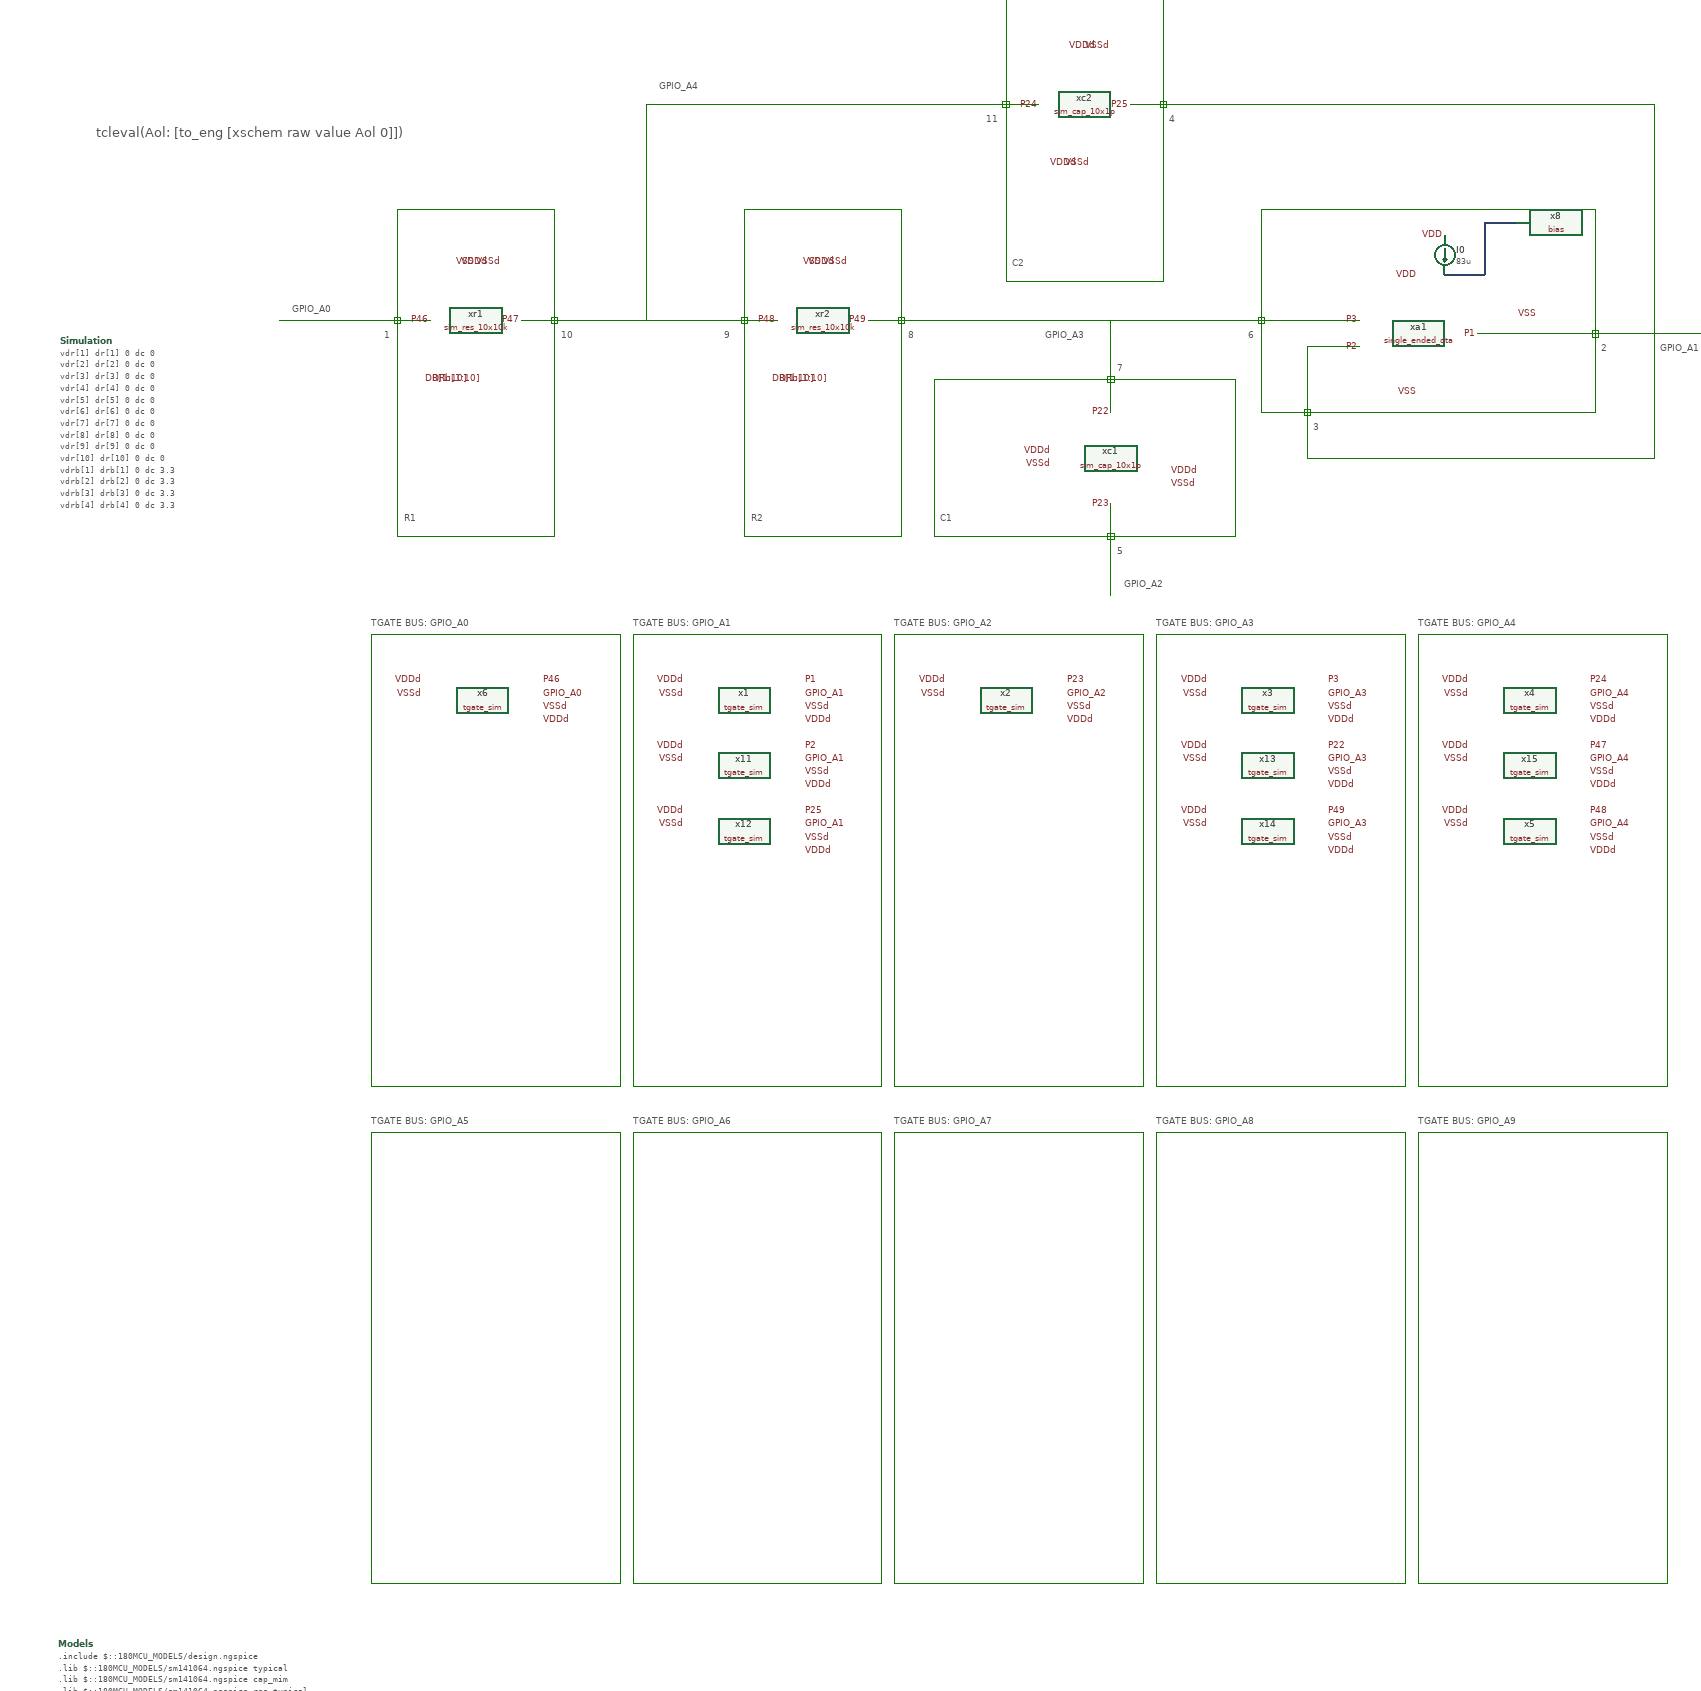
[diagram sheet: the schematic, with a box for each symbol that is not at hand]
v {xschem version=3.4.7 file_version=1.2}
G {}
K {}
V {}
S {}
E {}
L 4 1930 -1930 1930 -1830 {dash=10}
L 4 2190 -1950 2370 -1950 {dash=10}
L 4 1930 -1930 2010 -1930 {dash=10}
L 4 1860 -1970 2010 -1970 {dash=10}
L 4 730 -1970 780 -1970 {dash=10}
L 4 540 -1970 590 -1970 {dash=10}
L 4 2370 -1950 2550 -1950 {dash=10}
L 4 2460 -1950 2460 -1760 {dash=10}
L 4 1930 -1830 1930 -1760 {dash=10}
L 4 1930 -1760 2460 -1760 {dash=10}
L 4 1310 -1970 1860 -1970 {dash=10
}
L 4 780 -1970 1070 -1970 {dash=10
}
L 4 1630 -1880 1630 -1830 {dash=10}
L 4 1630 -1690 1630 -1640 {dash=10}
L 4 1630 -1970 1630 -1880 {dash=10}
L 4 1630 -1640 1630 -1550 {dash=10}
L 4 1470 -2300 1520 -2300 {dash=10}
L 4 1660 -2300 1710 -2300 {dash=10}
L 4 920 -2300 1470 -2300 {dash=10}
L 4 1710 -2300 2460 -2300 {dash=10}
L 4 920 -2300 920 -1970 {dash=10}
L 4 2460 -2300 2460 -1950 {dash=10}
L 4 360 -1970 540 -1970 {dash=10}
L 4 1260 -1970 1310 -1970 {dash=10}
L 4 1070 -1970 1120 -1970 {dash=10}
B 2 2650 -580 3450 -180 {flags=graph
y1=-2.8493778
y2=0.7426882
ypos1=0
ypos2=2
divy=5
subdivy=1
unity=1
x2=15.040264
divx=5
subdivx=8
xlabmag=1.0
ylabmag=1.0
node="\\"R=10k; gpio_a1 db20()\\"%0
\\"R=20k; gpio_a1 db20()\\"%1
\\"R=30k; gpio_a1 db20()\\"%2
\\"R=40k; gpio_a1 db20()\\"%3
\\"R=50k; gpio_a1 db20()\\"%4
\\"R=60k; gpio_a1 db20()\\"%5
\\"R=70k; gpio_a1 db20()\\"%6
\\"R=80k; gpio_a1 db20()\\"%7
\\"R=90k; gpio_a1 db20()\\"%8
\\"R=100k; gpio_a1 db20()\\"%9"
color="4 5 6 7 8 9 10 11 12 13"
dataset=-1
unitx=1
logx=1
logy=0
x1=-4.9302539
hcursor1_y=-3
}
B 4 1925 -1835 1935 -1825 {}
B 4 2365 -1955 2375 -1945 {}
B 4 1855 -1975 1865 -1965 {}
B 4 1305 -1975 1315 -1965 {}
B 4 1065 -1975 1075 -1965 {}
B 4 775 -1975 785 -1965 {}
B 4 1625 -1885 1635 -1875 {}
B 4 1625 -1645 1635 -1635 {}
B 4 1465 -2305 1475 -2295 {}
B 4 1705 -2305 1715 -2295 {}
B 4 535 -1975 545 -1965 {}
P 4 5 1860 -2140 1860 -1830 2370 -1830 2370 -2140 1860 -2140 {}
P 4 5 1070 -2140 1070 -1640 1310 -1640 1310 -2140 1070 -2140 {}
P 4 5 540 -2140 540 -1640 780 -1640 780 -2140 540 -2140 {}
P 4 5 1360 -1880 1360 -1640 1820 -1640 1820 -1880 1360 -1880 {}
P 4 5 1470 -2030 1710 -2030 1710 -2490 1470 -2490 1470 -2030 {}
P 4 5 500 -1490 500 -800 880 -800 880 -1490 500 -1490 {}
P 4 5 900 -1490 900 -800 1280 -800 1280 -1490 900 -1490 {}
P 4 5 1300 -1490 1300 -800 1680 -800 1680 -1490 1300 -1490 {}
P 4 5 1700 -1490 1700 -800 2080 -800 2080 -1490 1700 -1490 {}
P 4 5 2100 -1490 2100 -800 2480 -800 2480 -1490 2100 -1490 {}
P 4 5 500 -730 500 -40 880 -40 880 -730 500 -730 {}
P 4 5 900 -730 900 -40 1280 -40 1280 -730 900 -730 {}
P 4 5 1300 -730 1300 -40 1680 -40 1680 -730 1300 -730 {}
P 4 5 1700 -730 1700 -40 2080 -40 2080 -730 1700 -730 {}
P 4 5 2100 -730 2100 -40 2480 -40 2480 -730 2100 -730 {}
T {GPIO_A1} 2470 -1940 0 0 0.4 0.4 {}
T {GPIO_A3} 1530 -1960 0 0 0.4 0.4 {}
T {GPIO_A4} 940 -2340 0 0 0.4 0.4 {}
T {1} 520 -1960 0 0 0.3 0.3 {layer=4}
T {GPIO_A2} 1650 -1580 0 0 0.4 0.4 {}
T {GPIO_A0} 380 -2000 0 0 0.4 0.4 {}
T {2} 2380 -1940 0 0 0.3 0.3 {layer=4}
T {3} 1940 -1820 0 0 0.3 0.3 {layer=4}
T {4} 1720 -2290 0 0 0.3 0.3 {layer=4}
T {5} 1640 -1630 0 0 0.3 0.3 {layer=4}
T {6} 1840 -1960 0 0 0.3 0.3 {layer=4}
T {7} 1640 -1910 0 0 0.3 0.3 {layer=4}
T {8} 1320 -1960 0 0 0.3 0.3 {layer=4}
T {9} 1040 -1960 0 0 0.3 0.3 {layer=4}
T {10} 790 -1960 0 0 0.3 0.3 {layer=4}
T {11} 1440 -2290 0 0 0.3 0.3 {layer=4}
T {R1} 550 -1680 0 0 0.4 0.4 {}
T {C1} 1370 -1680 0 0 0.4 0.4 {}
T {C2} 1480 -2070 0 0 0.4 0.4 {}
T {TGATE BUS: GPIO_A0} 500 -1520 0 0 0.4 0.4 {}
T {TGATE BUS: GPIO_A1} 900 -1520 0 0 0.4 0.4 {}
T {TGATE BUS: GPIO_A2} 1300 -1520 0 0 0.4 0.4 {}
T {TGATE BUS: GPIO_A3} 1700 -1520 0 0 0.4 0.4 {}
T {TGATE BUS: GPIO_A4} 2100 -1520 0 0 0.4 0.4 {}
T {TGATE BUS: GPIO_A5} 500 -760 0 0 0.4 0.4 {}
T {TGATE BUS: GPIO_A6} 900 -760 0 0 0.4 0.4 {}
T {TGATE BUS: GPIO_A7} 1300 -760 0 0 0.4 0.4 {}
T {TGATE BUS: GPIO_A8} 1700 -760 0 0 0.4 0.4 {}
T {TGATE BUS: GPIO_A9} 2100 -760 0 0 0.4 0.4 {}
T {R2} 1080 -1680 0 0 0.4 0.4 {}
T {tcleval(Aol: [to_eng [xschem raw value Aol 0]])} 80 -2270 0 0 0.6 0.6 {floater=1}
N 2140 -2040 2200 -2040 {lab=#net1}
N 2200 -2120 2200 -2040 {lab=#net1}
N 2200 -2120 2250 -2120 {lab=#net1}
C {libs/core_analog/single_ended_ota/single_ended_ota.sym} 2100 -1950 0 0 {name=xa1}
C {libs/core_switch_matrix/tgate_sim/tgate_sim.sym} 670 -1390 0 0 {name=x6}
C {lab_pin.sym} 2190 -1950 3 1 {name=p1 sig_type=std_logic lab=P1}
C {lab_pin.sym} 2010 -1930 3 0 {name=p2 sig_type=std_logic lab=P2}
C {lab_pin.sym} 2100 -1860 0 0 {name=p23 sig_type=std_logic lab=VSS}
C {lab_pin.sym} 2100 -2040 0 0 {name=p24 sig_type=std_logic lab=VDD}
C {libs/core_passive_array/sim_cap_10x1p/sim_cap_10x1p.sym} 1630 -1760 0 0 {name=xc1}
C {lab_pin.sym} 1630 -1830 0 0 {name=p52 sig_type=std_logic lab=P22}
C {lab_pin.sym} 1630 -1690 0 0 {name=p53 sig_type=std_logic lab=P23}
C {lab_pin.sym} 1720 -1740 0 1 {name=p54 sig_type=std_logic lab=VDDd}
C {lab_pin.sym} 1720 -1720 0 1 {name=p55 sig_type=std_logic lab=VSSd}
C {lab_pin.sym} 580 -1420 0 0 {name=p68 sig_type=std_logic lab=VDDd}
C {lab_pin.sym} 580 -1400 0 0 {name=p69 sig_type=std_logic lab=VSSd}
C {lab_pin.sym} 760 -1420 0 1 {name=p70 sig_type=std_logic lab=P46}
C {lab_pin.sym} 760 -1400 0 1 {name=p71 sig_type=std_logic lab=GPIO_A0}
C {lab_pin.sym} 760 -1360 0 1 {name=p72 sig_type=std_logic lab=VDDd}
C {lab_pin.sym} 760 -1380 0 1 {name=p73 sig_type=std_logic lab=VSSd}
C {isource.sym} 2140 -2070 0 0 {name=I0 value=83u}
C {lab_pin.sym} 2140 -2100 0 0 {name=p191 sig_type=std_logic lab=VDD}
C {devices/code_shown.sym} 25 -1938.75 0 0 {name=Simulation only_toplevel=false value="
vdr[1] dr[1] 0 dc 0
vdr[2] dr[2] 0 dc 0
vdr[3] dr[3] 0 dc 0
vdr[4] dr[4] 0 dc 0
vdr[5] dr[5] 0 dc 0

vdr[6] dr[6] 0 dc 0
vdr[7] dr[7] 0 dc 0
vdr[8] dr[8] 0 dc 0
vdr[9] dr[9] 0 dc 0
vdr[10] dr[10] 0 dc 0

vdrb[1] drb[1] 0 dc 3.3
vdrb[2] drb[2] 0 dc 3.3
vdrb[3] drb[3] 0 dc 3.3
vdrb[4] drb[4] 0 dc 3.3
vdrb[5] drb[5] 0 dc 3.3

vdrb[6] drb[6] 0 dc 3.3
vdrb[7] drb[7] 0 dc 3.3
vdrb[8] drb[8] 0 dc 3.3
vdrb[9] drb[9] 0 dc 3.3
vdrb[10] drb[10] 0 dc 3.3


vvdd VDD 0 dc 3.3
vvss VSS 0 dc 0

vvddd VDDd 0 dc 3.3
vvssd VSSd 0 dc 0

vgpio_a2 GPIO_A2 0 dc 0
vgpio_a0 GPIO_A0 0 dc 1.65 ac 1

.nodeset all=3.3
.control
alter vdr[1] = 3.3
alter vdrb[1] = 0
save GPIO_A1
ac dec 1000 1 100e6
write sim_lk_lpf_2ord_4psv.raw
set appendwrite

reset
alter vdr[2] = 3.3
alter vdrb[2] = 0
save GPIO_A1
ac dec 1000 1 100e6
write sim_lk_lpf_2ord_4psv.raw

reset
alter vdr[3] = 3.3
alter vdrb[3] = 0
save GPIO_A1
ac dec 1000 1 100e6
write sim_lk_lpf_2ord_4psv.raw

reset
alter vdr[4] = 3.3
alter vdrb[4] = 0
save GPIO_A1
ac dec 1000 1 100e6
write sim_lk_lpf_2ord_4psv.raw

reset
alter vdr[5] = 3.3
alter vdrb[5] = 0
save GPIO_A1
ac dec 1000 1 100e6
write sim_lk_lpf_2ord_4psv.raw

reset
alter vdr[6] = 3.3
alter vdrb[6] = 0
save GPIO_A1
ac dec 1000 1 100e6
write sim_lk_lpf_2ord_4psv.raw

reset
alter vdr[7] = 3.3
alter vdrb[7] = 0
save GPIO_A1
ac dec 1000 1 100e6
write sim_lk_lpf_2ord_4psv.raw

reset
alter vdr[8] = 3.3
alter vdrb[8] = 0
save GPIO_A1
ac dec 1000 1 100e6
write sim_lk_lpf_2ord_4psv.raw

reset
alter vdr[9] = 3.3
alter vdrb[9] = 0
save GPIO_A1
ac dec 1000 1 100e6
write sim_lk_lpf_2ord_4psv.raw

reset
alter vdr[10] = 3.3
alter vdrb[10] = 0
save GPIO_A1
ac dec 1000 1 100e6
write sim_lk_lpf_2ord_4psv.raw
.endc
"}
C {devices/code_shown.sym} 22.5 52.5 0 0 {name=Models only_toplevel=false
format="tcleval( @value )"
value="
.include $::180MCU_MODELS/design.ngspice
.lib $::180MCU_MODELS/sm141064.ngspice typical
.lib $::180MCU_MODELS/sm141064.ngspice cap_mim
.lib $::180MCU_MODELS/sm141064.ngspice res_typical
.lib $::180MCU_MODELS/sm141064.ngspice moscap_typical
.lib $::180MCU_MODELS/sm141064.ngspice mimcap_typical
.include /foss/pdks/gf180mcuD/libs.ref/gf180mcu_fd_sc_mcu9t5v0/spice/gf180mcu_fd_sc_mcu9t5v0.spice
"}
C {launcher.sym} 2710 -150 0 0 {name=h5
descr="load waves" 
tclcommand="xschem raw_read $netlist_dir/sim_filter_block_tgate.raw ac"
}
C {lab_pin.sym} 2010 -1970 1 0 {name=p6 sig_type=std_logic lab=P3}
C {libs/core_passive_array/sim_res_10x10k/sim_res_10x10k.sym} 660 -1970 3 0 {name=xr1}
C {lab_pin.sym} 590 -1970 3 0 {name=p204 sig_type=std_logic lab=P46}
C {lab_pin.sym} 730 -1970 3 0 {name=p205 sig_type=std_logic lab=P47}
C {lab_pin.sym} 660 -2060 3 1 {name=p211 sig_type=std_logic lab=VSS}
C {lab_pin.sym} 680 -2060 3 1 {name=p212 sig_type=std_logic lab=VDDd}
C {lab_pin.sym} 700 -2060 3 1 {name=p213 sig_type=std_logic lab=VSSd}
C {lab_pin.sym} 650 -1880 3 0 {name=p214 sig_type=std_logic lab="DR[1:10]"}
C {lab_pin.sym} 670 -1880 3 0 {name=p215 sig_type=std_logic lab="DRb[1:10]"}
C {libs/core_passive_array/sim_cap_10x1p/sim_cap_10x1p.sym} 1590 -2300 3 0 {name=xc2}
C {lab_pin.sym} 1520 -2300 3 0 {name=p218 sig_type=std_logic lab=P24}
C {lab_pin.sym} 1660 -2300 3 0 {name=p219 sig_type=std_logic lab=P25}
C {lab_pin.sym} 1610 -2390 3 1 {name=p220 sig_type=std_logic lab=VDDd}
C {lab_pin.sym} 1630 -2390 3 1 {name=p221 sig_type=std_logic lab=VSSd}
C {libs/core_switch_matrix/tgate_sim/tgate_sim.sym} 1070 -1390 0 0 {name=x1}
C {lab_pin.sym} 980 -1420 0 0 {name=p3 sig_type=std_logic lab=VDDd}
C {lab_pin.sym} 980 -1400 0 0 {name=p4 sig_type=std_logic lab=VSSd}
C {lab_pin.sym} 1160 -1420 0 1 {name=p5 sig_type=std_logic lab=P1}
C {lab_pin.sym} 1160 -1400 0 1 {name=p7 sig_type=std_logic lab=GPIO_A1}
C {lab_pin.sym} 1160 -1360 0 1 {name=p8 sig_type=std_logic lab=VDDd}
C {lab_pin.sym} 1160 -1380 0 1 {name=p9 sig_type=std_logic lab=VSSd}
C {libs/core_switch_matrix/tgate_sim/tgate_sim.sym} 1470 -1390 0 0 {name=x2}
C {lab_pin.sym} 1380 -1420 0 0 {name=p10 sig_type=std_logic lab=VDDd}
C {lab_pin.sym} 1380 -1400 0 0 {name=p11 sig_type=std_logic lab=VSSd}
C {lab_pin.sym} 1560 -1420 0 1 {name=p16 sig_type=std_logic lab=P23}
C {lab_pin.sym} 1560 -1400 0 1 {name=p17 sig_type=std_logic lab=GPIO_A2}
C {lab_pin.sym} 1560 -1360 0 1 {name=p18 sig_type=std_logic lab=VDDd}
C {lab_pin.sym} 1560 -1380 0 1 {name=p19 sig_type=std_logic lab=VSSd}
C {libs/core_switch_matrix/tgate_sim/tgate_sim.sym} 1870 -1390 0 0 {name=x3}
C {lab_pin.sym} 1780 -1420 0 0 {name=p20 sig_type=std_logic lab=VDDd}
C {lab_pin.sym} 1780 -1400 0 0 {name=p21 sig_type=std_logic lab=VSSd}
C {lab_pin.sym} 1960 -1420 0 1 {name=p22 sig_type=std_logic lab=P3}
C {lab_pin.sym} 1960 -1400 0 1 {name=p31 sig_type=std_logic lab=GPIO_A3}
C {lab_pin.sym} 1960 -1360 0 1 {name=p32 sig_type=std_logic lab=VDDd}
C {lab_pin.sym} 1960 -1380 0 1 {name=p33 sig_type=std_logic lab=VSSd}
C {libs/core_switch_matrix/tgate_sim/tgate_sim.sym} 2270 -1390 0 0 {name=x4}
C {lab_pin.sym} 2360 -1420 0 1 {name=p34 sig_type=std_logic lab=P24}
C {lab_pin.sym} 2360 -1400 0 1 {name=p35 sig_type=std_logic lab=GPIO_A4}
C {lab_pin.sym} 2360 -1360 0 1 {name=p36 sig_type=std_logic lab=VDDd}
C {lab_pin.sym} 2360 -1380 0 1 {name=p37 sig_type=std_logic lab=VSSd}
C {libs/core_switch_matrix/tgate_sim/tgate_sim.sym} 1070 -1290 0 0 {name=x11}
C {lab_pin.sym} 980 -1320 0 0 {name=p82 sig_type=std_logic lab=VDDd}
C {lab_pin.sym} 980 -1300 0 0 {name=p83 sig_type=std_logic lab=VSSd}
C {lab_pin.sym} 1160 -1320 0 1 {name=p84 sig_type=std_logic lab=P2}
C {lab_pin.sym} 1160 -1300 0 1 {name=p85 sig_type=std_logic lab=GPIO_A1}
C {lab_pin.sym} 1160 -1260 0 1 {name=p86 sig_type=std_logic lab=VDDd}
C {lab_pin.sym} 1160 -1280 0 1 {name=p87 sig_type=std_logic lab=VSSd}
C {libs/core_switch_matrix/tgate_sim/tgate_sim.sym} 1070 -1190 0 0 {name=x12}
C {lab_pin.sym} 980 -1220 0 0 {name=p88 sig_type=std_logic lab=VDDd}
C {lab_pin.sym} 980 -1200 0 0 {name=p89 sig_type=std_logic lab=VSSd}
C {lab_pin.sym} 1160 -1220 0 1 {name=p90 sig_type=std_logic lab=P25}
C {lab_pin.sym} 1160 -1200 0 1 {name=p91 sig_type=std_logic lab=GPIO_A1}
C {lab_pin.sym} 1160 -1160 0 1 {name=p92 sig_type=std_logic lab=VDDd}
C {lab_pin.sym} 1160 -1180 0 1 {name=p93 sig_type=std_logic lab=VSSd}
C {libs/core_switch_matrix/tgate_sim/tgate_sim.sym} 1870 -1290 0 0 {name=x13}
C {lab_pin.sym} 1780 -1320 0 0 {name=p94 sig_type=std_logic lab=VDDd}
C {lab_pin.sym} 1780 -1300 0 0 {name=p95 sig_type=std_logic lab=VSSd}
C {lab_pin.sym} 1960 -1320 0 1 {name=p96 sig_type=std_logic lab=P22}
C {lab_pin.sym} 1960 -1300 0 1 {name=p97 sig_type=std_logic lab=GPIO_A3}
C {lab_pin.sym} 1960 -1260 0 1 {name=p98 sig_type=std_logic lab=VDDd}
C {lab_pin.sym} 1960 -1280 0 1 {name=p99 sig_type=std_logic lab=VSSd}
C {libs/core_switch_matrix/tgate_sim/tgate_sim.sym} 1870 -1190 0 0 {name=x14}
C {lab_pin.sym} 1780 -1220 0 0 {name=p100 sig_type=std_logic lab=VDDd}
C {lab_pin.sym} 1780 -1200 0 0 {name=p101 sig_type=std_logic lab=VSSd}
C {lab_pin.sym} 1960 -1220 0 1 {name=p102 sig_type=std_logic lab=P49}
C {lab_pin.sym} 1960 -1200 0 1 {name=p103 sig_type=std_logic lab=GPIO_A3}
C {lab_pin.sym} 1960 -1160 0 1 {name=p104 sig_type=std_logic lab=VDDd}
C {lab_pin.sym} 1960 -1180 0 1 {name=p105 sig_type=std_logic lab=VSSd}
C {lab_pin.sym} 2180 -1420 0 0 {name=p106 sig_type=std_logic lab=VDDd}
C {lab_pin.sym} 2180 -1400 0 0 {name=p107 sig_type=std_logic lab=VSSd}
C {libs/core_switch_matrix/tgate_sim/tgate_sim.sym} 2270 -1290 0 0 {name=x15}
C {lab_pin.sym} 2360 -1320 0 1 {name=p108 sig_type=std_logic lab=P47}
C {lab_pin.sym} 2360 -1300 0 1 {name=p109 sig_type=std_logic lab=GPIO_A4}
C {lab_pin.sym} 2360 -1260 0 1 {name=p110 sig_type=std_logic lab=VDDd}
C {lab_pin.sym} 2360 -1280 0 1 {name=p111 sig_type=std_logic lab=VSSd}
C {lab_pin.sym} 2180 -1320 0 0 {name=p112 sig_type=std_logic lab=VDDd}
C {lab_pin.sym} 2180 -1300 0 0 {name=p113 sig_type=std_logic lab=VSSd}
C {libs/core_passive_array/sim_res_10x10k/sim_res_10x10k.sym} 1190 -1970 3 0 {name=xr2}
C {lab_pin.sym} 1120 -1970 3 0 {name=p50 sig_type=std_logic lab=P48}
C {lab_pin.sym} 1260 -1970 3 0 {name=p51 sig_type=std_logic lab=P49}
C {lab_pin.sym} 1190 -2060 3 1 {name=p58 sig_type=std_logic lab=VSS}
C {lab_pin.sym} 1210 -2060 3 1 {name=p59 sig_type=std_logic lab=VDDd}
C {lab_pin.sym} 1230 -2060 3 1 {name=p64 sig_type=std_logic lab=VSSd}
C {libs/core_switch_matrix/tgate_sim/tgate_sim.sym} 2270 -1190 0 0 {name=x5}
C {lab_pin.sym} 2360 -1220 0 1 {name=p12 sig_type=std_logic lab=P48}
C {lab_pin.sym} 2360 -1200 0 1 {name=p13 sig_type=std_logic lab=GPIO_A4}
C {lab_pin.sym} 2360 -1160 0 1 {name=p14 sig_type=std_logic lab=VDDd}
C {lab_pin.sym} 2360 -1180 0 1 {name=p15 sig_type=std_logic lab=VSSd}
C {lab_pin.sym} 2180 -1220 0 0 {name=p25 sig_type=std_logic lab=VDDd}
C {lab_pin.sym} 2180 -1200 0 0 {name=p26 sig_type=std_logic lab=VSSd}
C {lab_pin.sym} 1180 -1880 3 0 {name=p27 sig_type=std_logic lab="DR[1:10]"}
C {lab_pin.sym} 1200 -1880 3 0 {name=p28 sig_type=std_logic lab="DRb[1:10]"}
C {lab_pin.sym} 1580 -2210 3 0 {name=p38 sig_type=std_logic lab="VDDd"}
C {lab_pin.sym} 1600 -2210 3 0 {name=p39 sig_type=std_logic lab="VSSd"}
C {lab_pin.sym} 1540 -1770 0 0 {name=p40 sig_type=std_logic lab="VDDd"}
C {lab_pin.sym} 1540 -1750 0 0 {name=p41 sig_type=std_logic lab="VSSd"}
C {libs/core_analog/single_ended_ota/bias.sym} 2250 -2040 0 0 {name=x8}
C {lab_pin.sym} 2250 -1980 0 1 {name=p67 sig_type=std_logic lab=VSS}
